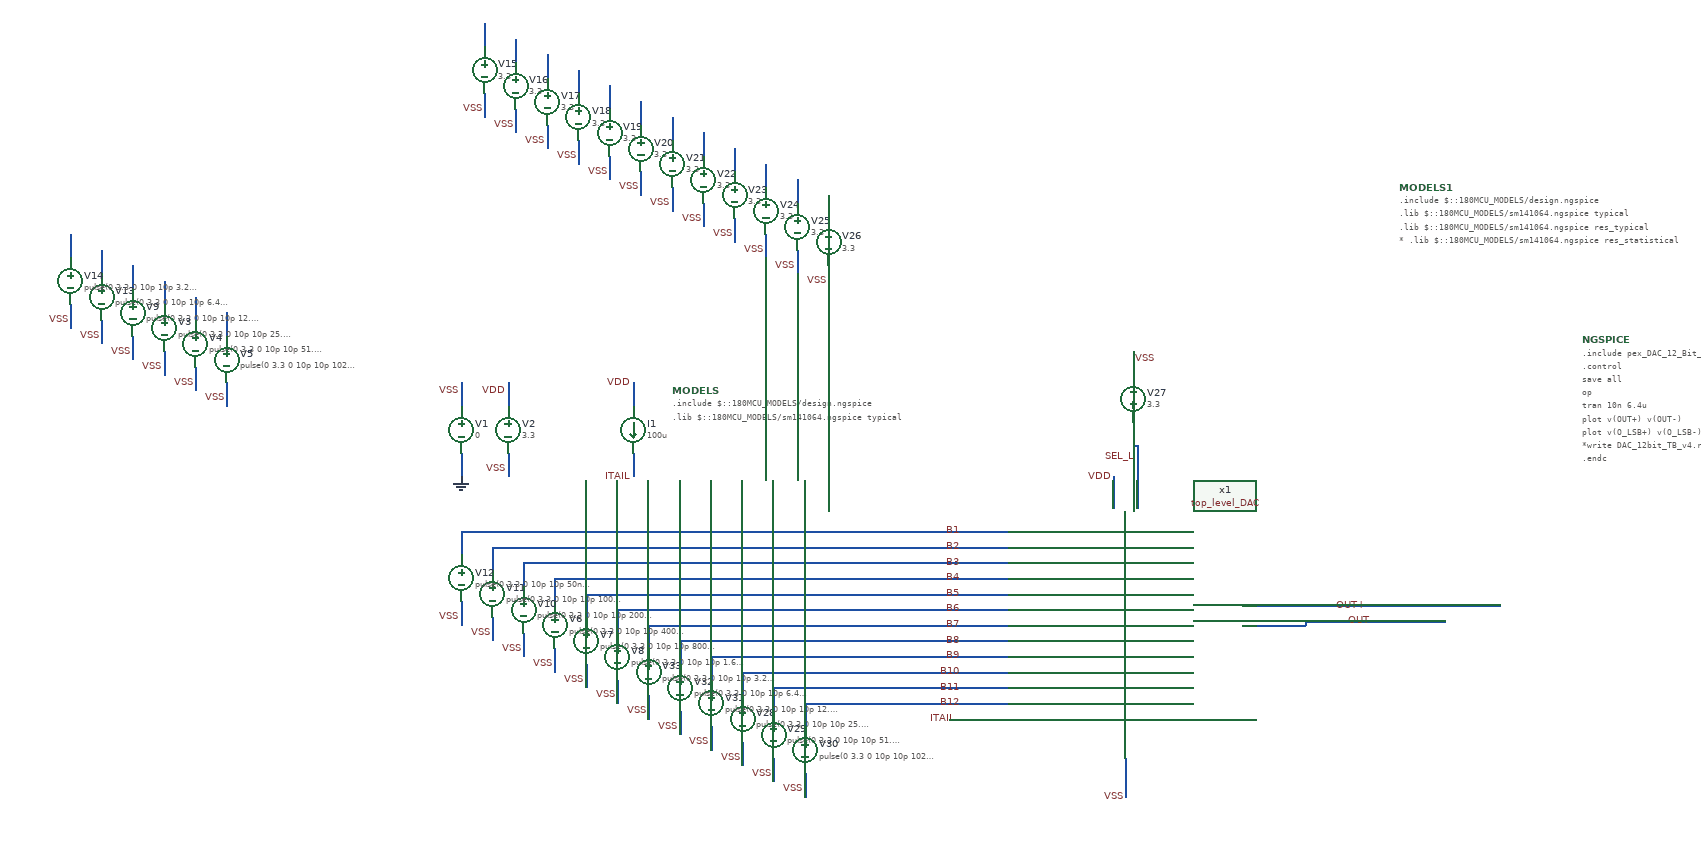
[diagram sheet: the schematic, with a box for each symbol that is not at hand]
v {xschem version=3.1.0 file_version=1.2
}
G {}
K {}
V {}
S {}
E {}
N 50 -450 50 -420 {
lab=GND}
N 50 -540 50 -510 {
lab=VSS}
N 110 -540 110 -510 {
lab=VDD}
N 110 -450 110 -420 {
lab=VSS}
N 170 -290 170 -260 {
lab=B4}
N 170 -200 170 -170 {
lab=VSS}
N 210 -270 210 -240 {
lab=B5}
N 210 -180 210 -150 {
lab=VSS}
N 250 -250 250 -220 {
lab=B6}
N 250 -160 250 -130 {
lab=VSS}
N 130 -310 130 -280 {
lab=B3}
N 130 -220 130 -190 {
lab=VSS}
N 90 -330 90 -300 {
lab=B2}
N 90 -240 90 -210 {
lab=VSS}
N 50 -350 50 -320 {
lab=B1}
N 50 -260 50 -230 {
lab=VSS}
N -330 -670 -330 -640 {
lab=#net1}
N -330 -580 -330 -550 {
lab=VSS}
N -290 -650 -290 -620 {
lab=#net2}
N -290 -560 -290 -530 {
lab=VSS}
N -250 -630 -250 -600 {
lab=#net3}
N -250 -540 -250 -510 {
lab=VSS}
N -370 -690 -370 -660 {
lab=#net4}
N -370 -600 -370 -570 {
lab=VSS}
N -410 -710 -410 -680 {
lab=#net5}
N -410 -620 -410 -590 {
lab=VSS}
N -450 -730 -450 -700 {
lab=#net6}
N -450 -640 -450 -610 {
lab=VSS}
N 270 -540 270 -510 {
lab=VDD}
N 270 -450 270 -420 {
lab=ITAIL}
N 50 -350 750 -350 {
lab=B1}
N 90 -330 750 -330 {
lab=B2}
N 130 -310 750 -310 {
lab=B3}
N 170 -290 750 -290 {
lab=B4}
N 210 -270 750 -270 {
lab=B5}
N 250 -250 750 -250 {
lab=B6}
N 290 -230 750 -230 {
lab=B7}
N 330 -210 750 -210 {
lab=B8}
N 370 -190 750 -190 {
lab=B9}
N 410 -170 750 -170 {
lab=B10}
N 450 -150 750 -150 {
lab=B11}
N 490 -130 750 -130 {
lab=B12}
N 885 -420 885 -380 {
lab=VDD}
N 900 -60 900 -10 {
lab=VSS}
N 1260 -235 1290 -235 {
lab=OUT-}
N 1290 -235 1310 -235 {
lab=OUT-}
N 1350 -255 1380 -255 {
lab=OUT+}
N 1230 -235 1260 -235 {
lab=OUT-}
N 1240 -255 1350 -255 {
lab=OUT+}
N 1210 -255 1240 -255 {
lab=OUT+}
N 1200 -235 1230 -235 {
lab=OUT-}
N 1140 -255 1210 -255 {
lab=OUT+}
N 1130 -235 1200 -235 {
lab=OUT-}
N 1120 -255 1140 -255 {
lab=OUT+}
N 1130 -235 1130 -230 {
lab=OUT-}
N 915 -405 915 -380 {
lab=SEL_L}
N 675 -110 750 -110 {
lab=ITAIL}
N 1110 -230 1130 -230 {
lab=OUT-}
N 1050 -255 1120 -255 {
lab=OUT+}
N 80 -1000 80 -970 {
lab=#net7}
N 80 -910 80 -880 {
lab=VSS}
N 120 -980 120 -950 {
lab=#net8}
N 120 -890 120 -860 {
lab=VSS}
N 160 -960 160 -930 {
lab=#net9}
N 160 -870 160 -840 {
lab=VSS}
N 200 -940 200 -910 {
lab=#net10}
N 200 -850 200 -820 {
lab=VSS}
N 240 -920 240 -890 {
lab=#net11}
N 240 -830 240 -800 {
lab=VSS}
N 280 -900 280 -870 {
lab=#net12}
N 280 -810 280 -780 {
lab=VSS}
N 320 -880 320 -850 {
lab=#net13}
N 320 -790 320 -760 {
lab=VSS}
N 360 -860 360 -830 {
lab=#net14}
N 360 -770 360 -740 {
lab=VSS}
N 400 -840 400 -810 {
lab=#net15}
N 400 -750 400 -720 {
lab=VSS}
N 440 -820 440 -790 {
lab=#net16}
N 440 -730 440 -700 {
lab=VSS}
N 480 -800 480 -770 {
lab=#net17}
N 480 -710 480 -680 {
lab=VSS}
N 520 -780 520 -750 {
lab=#net18}
N 520 -690 520 -660 {
lab=VSS}
N 910 -490 910 -460 {
lab=SEL_L}
N 910 -580 910 -550 {
lab=VSS}
N 910 -460 915 -460 {
lab=SEL_L}
N 915 -460 915 -405 {
lab=SEL_L}
N 1050 -230 1110 -230 {
lab=OUT-}
N 410 -170 410 -140 {
lab=B10}
N 410 -80 410 -50 {
lab=VSS}
N 450 -150 450 -120 {
lab=B11}
N 450 -60 450 -30 {
lab=VSS}
N 490 -130 490 -100 {
lab=B12}
N 490 -40 490 -10 {
lab=VSS}
N 370 -190 370 -160 {
lab=B9}
N 370 -100 370 -70 {
lab=VSS}
N 330 -210 330 -180 {
lab=B8}
N 330 -120 330 -90 {
lab=VSS}
N 290 -230 290 -200 {
lab=B7}
N 290 -140 290 -110 {
lab=VSS}
C {devices/vsource.sym} 50 -480 0 0 {name=V1 value=0}
C {devices/vsource.sym} 110 -480 0 0 {name=V2 value=3.3}
C {devices/gnd.sym} 50 -420 0 0 {name=l1 lab=GND}
C {devices/lab_wire.sym} 50 -530 0 0 {name=p1 sig_type=std_logic lab=VSS}
C {devices/lab_wire.sym} 110 -530 0 0 {name=p4 sig_type=std_logic lab=VDD}
C {devices/lab_wire.sym} 110 -430 0 0 {name=p8 sig_type=std_logic lab=VSS}
C {devices/vsource.sym} 170 -230 0 0 {name=V6 value="pulse(0 3.3 0 10p 10p 400n 800n)"}
C {devices/lab_wire.sym} 170 -180 0 0 {name=p15 sig_type=std_logic lab=VSS}
C {devices/vsource.sym} 210 -210 0 0 {name=V7 value="pulse(0 3.3 0 10p 10p 800n 1.6u)"}
C {devices/lab_wire.sym} 210 -160 0 0 {name=p17 sig_type=std_logic lab=VSS}
C {devices/vsource.sym} 250 -190 0 0 {name=V8 value="pulse(0 3.3 0 10p 10p 1.6u 3.2u)"}
C {devices/lab_wire.sym} 250 -140 0 0 {name=p19 sig_type=std_logic lab=VSS}
C {devices/vsource.sym} 130 -250 0 0 {name=V10 value="pulse(0 3.3 0 10p 10p 200n 400n)"}
C {devices/lab_wire.sym} 130 -200 0 0 {name=p23 sig_type=std_logic lab=VSS}
C {devices/vsource.sym} 90 -270 0 0 {name=V11 value="pulse(0 3.3 0 10p 10p 100n 200n)"}
C {devices/lab_wire.sym} 90 -220 0 0 {name=p25 sig_type=std_logic lab=VSS}
C {devices/vsource.sym} 50 -290 0 0 {name=V12 value="pulse(0 3.3 0 10p 10p 50n 100n)"}
C {devices/lab_wire.sym} 50 -240 0 0 {name=p27 sig_type=std_logic lab=VSS}
C {devices/lab_wire.sym} -330 -560 0 0 {name=p2 sig_type=std_logic lab=VSS}
C {devices/lab_wire.sym} -290 -540 0 0 {name=p3 sig_type=std_logic lab=VSS}
C {devices/lab_wire.sym} -250 -520 0 0 {name=p5 sig_type=std_logic lab=VSS}
C {devices/lab_wire.sym} -370 -580 0 0 {name=p6 sig_type=std_logic lab=VSS}
C {devices/vsource.sym} -410 -650 0 0 {name=V13 value="pulse(0 3.3 0 10p 10p 6.4u 12.8u)"}
C {devices/lab_wire.sym} -410 -600 0 0 {name=p7 sig_type=std_logic lab=VSS}
C {devices/vsource.sym} -450 -670 0 0 {name=V14 value="pulse(0 3.3 0 10p 10p 3.2u 6.4u)"}
C {devices/lab_wire.sym} -450 -620 0 0 {name=p10 sig_type=std_logic lab=VSS}
C {devices/isource.sym} 270 -480 0 0 {name=I1 value=100u}
C {devices/lab_wire.sym} 270 -540 0 0 {name=p12 sig_type=std_logic lab=VDD}
C {devices/lab_wire.sym} 270 -420 0 0 {name=p13 sig_type=std_logic lab=ITAIL}
C {devices/lab_wire.sym} 885 -420 0 0 {name=p14 sig_type=std_logic lab=VDD}
C {devices/lab_wire.sym} 900 -10 0 0 {name=p16 sig_type=std_logic lab=VSS}
C {devices/code_shown.sym} 320 -530 0 0 {name=MODELS only_toplevel=true
format="tcleval( @value )"
value="
.include $::180MCU_MODELS/design.ngspice
.lib $::180MCU_MODELS/sm141064.ngspice typical
"}
C {devices/code_shown.sym} 1485 -595 0 1 {name=NGSPICE only_toplevel=true

value="

.include "pex_DAC_12_Bit_V4.spice"
.control
save all
op

tran 10n 6.4u
plot v(OUT+) v(OUT-)
plot v(O_LSB+) v(O_LSB-)
*write DAC_12bit_TB_v4.raw
.endc
"}
C {devices/lab_wire.sym} 685 -110 0 0 {name=p9 sig_type=std_logic lab=ITAIL}
C {devices/vsource.sym} -370 -630 0 0 {name=V9 value="pulse(0 3.3 0 10p 10p 12.8u 25.6u)"}
C {devices/vsource.sym} -330 -610 0 0 {name=V3 value="pulse(0 3.3 0 10p 10p 25.6u 51.2u)"}
C {devices/vsource.sym} -290 -590 0 0 {name=V4 value="pulse(0 3.3 0 10p 10p 51.2u 102.4u)"}
C {devices/vsource.sym} -250 -570 0 0 {name=V5 value="pulse(0 3.3 0 10p 10p 102.4u 204.8u)"}
C {devices/vsource.sym} 80 -940 0 0 {name=V15 value=3.3}
C {devices/lab_wire.sym} 80 -890 0 0 {name=p18 sig_type=std_logic lab=VSS}
C {devices/vsource.sym} 120 -920 0 0 {name=V16 value=3.3}
C {devices/lab_wire.sym} 120 -870 0 0 {name=p11 sig_type=std_logic lab=VSS}
C {devices/vsource.sym} 160 -900 0 0 {name=V17 value=3.3}
C {devices/lab_wire.sym} 160 -850 0 0 {name=p20 sig_type=std_logic lab=VSS}
C {devices/vsource.sym} 200 -880 0 0 {name=V18 value=3.3}
C {devices/lab_wire.sym} 200 -830 0 0 {name=p28 sig_type=std_logic lab=VSS}
C {devices/vsource.sym} 240 -860 0 0 {name=V19 value=3.3}
C {devices/lab_wire.sym} 240 -810 0 0 {name=p29 sig_type=std_logic lab=VSS}
C {devices/vsource.sym} 280 -840 0 0 {name=V20 value=3.3}
C {devices/lab_wire.sym} 280 -790 0 0 {name=p30 sig_type=std_logic lab=VSS}
C {devices/vsource.sym} 320 -820 0 0 {name=V21 value=3.3}
C {devices/lab_wire.sym} 320 -770 0 0 {name=p31 sig_type=std_logic lab=VSS}
C {devices/vsource.sym} 360 -800 0 0 {name=V22 value=3.3}
C {devices/lab_wire.sym} 360 -750 0 0 {name=p32 sig_type=std_logic lab=VSS}
C {devices/vsource.sym} 400 -780 0 0 {name=V23 value=3.3}
C {devices/lab_wire.sym} 400 -730 0 0 {name=p33 sig_type=std_logic lab=VSS}
C {devices/vsource.sym} 440 -760 0 0 {name=V24 value=3.3}
C {devices/lab_wire.sym} 440 -710 0 0 {name=p34 sig_type=std_logic lab=VSS}
C {devices/vsource.sym} 480 -740 0 0 {name=V25 value=3.3}
C {devices/lab_wire.sym} 480 -690 0 0 {name=p35 sig_type=std_logic lab=VSS}
C {devices/vsource.sym} 520 -720 0 0 {name=V26 value=3.3}
C {devices/lab_wire.sym} 520 -670 0 0 {name=p36 sig_type=std_logic lab=VSS}
C {devices/lab_wire.sym} 690 -350 0 0 {name=p37 sig_type=std_logic lab=B1}
C {devices/lab_wire.sym} 690 -330 0 0 {name=p38 sig_type=std_logic lab=B2}
C {devices/lab_wire.sym} 690 -310 0 0 {name=p39 sig_type=std_logic lab=B3}
C {devices/lab_wire.sym} 690 -290 0 0 {name=p40 sig_type=std_logic lab=B4}
C {devices/lab_wire.sym} 690 -270 0 0 {name=p41 sig_type=std_logic lab=B5}
C {devices/lab_wire.sym} 690 -250 0 0 {name=p42 sig_type=std_logic lab=B6}
C {devices/lab_wire.sym} 690 -230 0 0 {name=p43 sig_type=std_logic lab=B7}
C {devices/lab_wire.sym} 690 -210 0 0 {name=p44 sig_type=std_logic lab=B8}
C {devices/lab_wire.sym} 690 -190 0 0 {name=p45 sig_type=std_logic lab=B9}
C {devices/lab_wire.sym} 690 -170 0 0 {name=p46 sig_type=std_logic lab=B10}
C {devices/lab_wire.sym} 690 -150 0 0 {name=p47 sig_type=std_logic lab=B11}
C {devices/lab_wire.sym} 690 -130 0 0 {name=p48 sig_type=std_logic lab=B12}
C {devices/vsource.sym} 910 -520 2 0 {name=V27 value=3.3}
C {devices/lab_wire.sym} 910 -570 2 0 {name=p49 sig_type=std_logic lab=VSS}
C {devices/lab_wire.sym} 915 -445 0 0 {name=p50 sig_type=std_logic lab=SEL_L}
C {devices/lab_pin.sym} 1210 -255 0 0 {name=p24 sig_type=std_logic lab=OUT+}
C {devices/lab_pin.sym} 1220 -235 0 0 {name=p26 sig_type=std_logic lab=OUT-}
C {devices/vsource.sym} 410 -110 0 0 {name=V28 value="pulse(0 3.3 0 10p 10p 25.6u 51.2u)"}
C {devices/lab_wire.sym} 410 -60 0 0 {name=p55 sig_type=std_logic lab=VSS}
C {devices/vsource.sym} 450 -90 0 0 {name=V29 value="pulse(0 3.3 0 10p 10p 51.2u 102.4u)"}
C {devices/lab_wire.sym} 450 -40 0 0 {name=p56 sig_type=std_logic lab=VSS}
C {devices/vsource.sym} 490 -70 0 0 {name=V30 value="pulse(0 3.3 0 10p 10p 102.4u 204.8u)"}
C {devices/lab_wire.sym} 490 -20 0 0 {name=p57 sig_type=std_logic lab=VSS}
C {devices/vsource.sym} 370 -130 0 0 {name=V31 value="pulse(0 3.3 0 10p 10p 12.8u 25.6u)"}
C {devices/lab_wire.sym} 370 -80 0 0 {name=p58 sig_type=std_logic lab=VSS}
C {devices/vsource.sym} 330 -150 0 0 {name=V32 value="pulse(0 3.3 0 10p 10p 6.4u 12.8u)"}
C {devices/lab_wire.sym} 330 -100 0 0 {name=p59 sig_type=std_logic lab=VSS}
C {devices/vsource.sym} 290 -170 0 0 {name=V33 value="pulse(0 3.3 0 10p 10p 3.2u 6.4u)"}
C {devices/lab_wire.sym} 290 -120 0 0 {name=p60 sig_type=std_logic lab=VSS}
C {top_level_DAC.sym} 900 -220 0 0 {name=x1}
C {devices/code_shown.sym} 1250 -790 0 0 {name=MODELS1 only_toplevel=true
format="tcleval( @value )"
value="
.include $::180MCU_MODELS/design.ngspice
.lib $::180MCU_MODELS/sm141064.ngspice typical
.lib $::180MCU_MODELS/sm141064.ngspice res_typical
* .lib $::180MCU_MODELS/sm141064.ngspice res_statistical
"}
